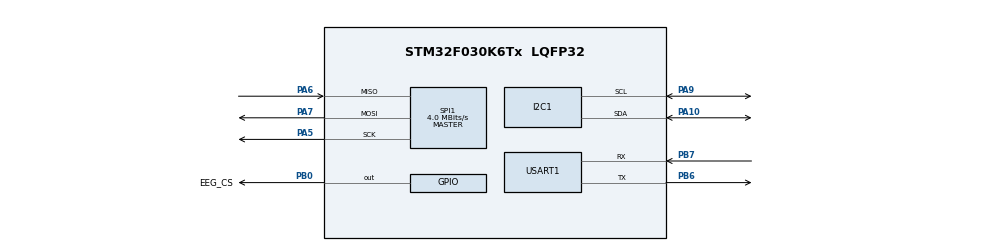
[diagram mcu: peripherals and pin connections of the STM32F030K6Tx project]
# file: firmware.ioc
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Mcu.Family=STM32F0
Mcu.Name=STM32F030K6Tx
Mcu.Package=LQFP32
PA10.Mode=I2C
PA10.Signal=I2C1_SDA
PA5.Mode=Full_Duplex_Master
PA5.Signal=SPI1_SCK
PA6.Mode=Full_Duplex_Master
PA6.Signal=SPI1_MISO
PA7.Mode=Full_Duplex_Master
PA7.Signal=SPI1_MOSI
PA9.Mode=I2C
PA9.Signal=I2C1_SCL
PB0.GPIO_Label=EEG_CS
PB0.Signal=GPIO_Output
PB6.Mode=Asynchronous
PB6.Signal=USART1_TX
PB7.Mode=Asynchronous
PB7.Signal=USART1_RX
ProjectManager.HeapSize=0x200
ProjectManager.StackSize=0x400
ProjectManager.TargetToolchain=Makefile
SPI1.CalculateBaudRate=4.0 MBits/s
SPI1.Direction=SPI_DIRECTION_2LINES
SPI1.Mode=SPI_MODE_MASTER
SPI1.VirtualType=VM_MASTER
USART1.VirtualMode-Asynchronous=VM_ASYNC
board=custom

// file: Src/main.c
/* USER CODE BEGIN Header */
/**
  ******************************************************************************
  * @file           : main.c
  * @brief          : Main program body
  ******************************************************************************
  ** This notice applies to any and all portions of this file
  * that are not between comment pairs USER CODE BEGIN and
  * USER CODE END. Other portions of this file, whether
  * inserted by the user or by software development tools
  * are owned by their respective copyright owners.
  *
  * COPYRIGHT(c) 2019 STMicroelectronics
  *
  * Redistribution and use in source and binary forms, with or without modification,
  * are permitted provided that the following conditions are met:
  *   1. Redistributions of source code must retain the above copyright notice,
  *      this list of conditions and the following disclaimer.
  *   2. Redistributions in binary form must reproduce the above copyright notice,
  *      this list of conditions and the following disclaimer in the documentation
  *      and/or other materials provided with the distribution.
  *   3. Neither the name of STMicroelectronics nor the names of its contributors
  *      may be used to endorse or promote products derived from this software
  *      without specific prior written permission.
  *
  * THIS SOFTWARE IS PROVIDED BY THE COPYRIGHT HOLDERS AND CONTRIBUTORS "AS IS"
  * AND ANY EXPRESS OR IMPLIED WARRANTIES, INCLUDING, BUT NOT LIMITED TO, THE
  * IMPLIED WARRANTIES OF MERCHANTABILITY AND FITNESS FOR A PARTICULAR PURPOSE ARE
  * DISCLAIMED. IN NO EVENT SHALL THE COPYRIGHT HOLDER OR CONTRIBUTORS BE LIABLE
  * FOR ANY DIRECT, INDIRECT, INCIDENTAL, SPECIAL, EXEMPLARY, OR CONSEQUENTIAL
  * DAMAGES (INCLUDING, BUT NOT LIMITED TO, PROCUREMENT OF SUBSTITUTE GOODS OR
  * SERVICES; LOSS OF USE, DATA, OR PROFITS; OR BUSINESS INTERRUPTION) HOWEVER
  * CAUSED AND ON ANY THEORY OF LIABILITY, WHETHER IN CONTRACT, STRICT LIABILITY,
  * OR TORT (INCLUDING NEGLIGENCE OR OTHERWISE) ARISING IN ANY WAY OUT OF THE USE
  * OF THIS SOFTWARE, EVEN IF ADVISED OF THE POSSIBILITY OF SUCH DAMAGE.
  *
  ******************************************************************************
  */
/* USER CODE END Header */

#include "main.h"

I2C_HandleTypeDef hi2c1;

SPI_HandleTypeDef hspi1;

UART_HandleTypeDef huart1;

void SystemClock_Config(void);
static void MX_GPIO_Init(void);
static void MX_I2C1_Init(void);
static void MX_SPI1_Init(void);
static void MX_USART1_UART_Init(void);

int main(void)
{

  /* MCU Configuration--------------------------------------------------------*/

  /* Reset of all peripherals, Initializes the Flash interface and the Systick. */
  HAL_Init();

  /* Configure the system clock */
  SystemClock_Config();

  /* Initialize all configured peripherals */
  MX_GPIO_Init();
  MX_I2C1_Init();
  MX_SPI1_Init();
  MX_USART1_UART_Init();

  /* Infinite loop */
  while (1)
  {

  }
}

void SystemClock_Config(void)
{
  RCC_OscInitTypeDef RCC_OscInitStruct = {0};
  RCC_ClkInitTypeDef RCC_ClkInitStruct = {0};
  RCC_PeriphCLKInitTypeDef PeriphClkInit = {0};

  /**Initializes the CPU, AHB and APB busses clocks
  */
  RCC_OscInitStruct.OscillatorType = RCC_OSCILLATORTYPE_HSI;
  RCC_OscInitStruct.HSIState = RCC_HSI_ON;
  RCC_OscInitStruct.HSICalibrationValue = RCC_HSICALIBRATION_DEFAULT;
  RCC_OscInitStruct.PLL.PLLState = RCC_PLL_NONE;
  if (HAL_RCC_OscConfig(&RCC_OscInitStruct) != HAL_OK)
  {
    Error_Handler();
  }
  /**Initializes the CPU, AHB and APB busses clocks
  */
  RCC_ClkInitStruct.ClockType = RCC_CLOCKTYPE_HCLK|RCC_CLOCKTYPE_SYSCLK
                              |RCC_CLOCKTYPE_PCLK1;
  RCC_ClkInitStruct.SYSCLKSource = RCC_SYSCLKSOURCE_HSI;
  RCC_ClkInitStruct.AHBCLKDivider = RCC_SYSCLK_DIV1;
  RCC_ClkInitStruct.APB1CLKDivider = RCC_HCLK_DIV1;

  if (HAL_RCC_ClockConfig(&RCC_ClkInitStruct, FLASH_LATENCY_0) != HAL_OK)
  {
    Error_Handler();
  }
  PeriphClkInit.PeriphClockSelection = RCC_PERIPHCLK_USART1|RCC_PERIPHCLK_I2C1;
  PeriphClkInit.Usart1ClockSelection = RCC_USART1CLKSOURCE_PCLK1;
  PeriphClkInit.I2c1ClockSelection = RCC_I2C1CLKSOURCE_HSI;
  if (HAL_RCCEx_PeriphCLKConfig(&PeriphClkInit) != HAL_OK)
  {
    Error_Handler();
  }
}

static void MX_I2C1_Init(void)
{

  hi2c1.Instance = I2C1;
  hi2c1.Init.Timing = 0x2000090E;
  hi2c1.Init.OwnAddress1 = 0;
  hi2c1.Init.AddressingMode = I2C_ADDRESSINGMODE_7BIT;
  hi2c1.Init.DualAddressMode = I2C_DUALADDRESS_DISABLE;
  hi2c1.Init.OwnAddress2 = 0;
  hi2c1.Init.OwnAddress2Masks = I2C_OA2_NOMASK;
  hi2c1.Init.GeneralCallMode = I2C_GENERALCALL_DISABLE;
  hi2c1.Init.NoStretchMode = I2C_NOSTRETCH_DISABLE;
  if (HAL_I2C_Init(&hi2c1) != HAL_OK)
  {
    Error_Handler();
  }
  /**Configure Analogue filter
  */
  if (HAL_I2CEx_ConfigAnalogFilter(&hi2c1, I2C_ANALOGFILTER_ENABLE) != HAL_OK)
  {
    Error_Handler();
  }
  /**Configure Digital filter
  */
  if (HAL_I2CEx_ConfigDigitalFilter(&hi2c1, 0) != HAL_OK)
  {
    Error_Handler();
  }

}

static void MX_SPI1_Init(void)
{

  /* SPI1 parameter configuration*/
  hspi1.Instance = SPI1;
  hspi1.Init.Mode = SPI_MODE_MASTER;
  hspi1.Init.Direction = SPI_DIRECTION_2LINES;
  hspi1.Init.DataSize = SPI_DATASIZE_4BIT;
  hspi1.Init.CLKPolarity = SPI_POLARITY_LOW;
  hspi1.Init.CLKPhase = SPI_PHASE_1EDGE;
  hspi1.Init.NSS = SPI_NSS_SOFT;
  hspi1.Init.BaudRatePrescaler = SPI_BAUDRATEPRESCALER_2;
  hspi1.Init.FirstBit = SPI_FIRSTBIT_MSB;
  hspi1.Init.TIMode = SPI_TIMODE_DISABLE;
  hspi1.Init.CRCCalculation = SPI_CRCCALCULATION_DISABLE;
  hspi1.Init.CRCPolynomial = 7;
  hspi1.Init.CRCLength = SPI_CRC_LENGTH_DATASIZE;
  hspi1.Init.NSSPMode = SPI_NSS_PULSE_ENABLE;
  if (HAL_SPI_Init(&hspi1) != HAL_OK)
  {
    Error_Handler();
  }

}

static void MX_USART1_UART_Init(void)
{

  huart1.Instance = USART1;
  huart1.Init.BaudRate = 38400;
  huart1.Init.WordLength = UART_WORDLENGTH_8B;
  huart1.Init.StopBits = UART_STOPBITS_1;
  huart1.Init.Parity = UART_PARITY_NONE;
  huart1.Init.Mode = UART_MODE_TX_RX;
  huart1.Init.HwFlowCtl = UART_HWCONTROL_NONE;
  huart1.Init.OverSampling = UART_OVERSAMPLING_16;
  huart1.Init.OneBitSampling = UART_ONE_BIT_SAMPLE_DISABLE;
  huart1.AdvancedInit.AdvFeatureInit = UART_ADVFEATURE_NO_INIT;
  if (HAL_UART_Init(&huart1) != HAL_OK)
  {
    Error_Handler();
  }

}

static void MX_GPIO_Init(void)
{
  GPIO_InitTypeDef GPIO_InitStruct = {0};

  /* GPIO Ports Clock Enable */
  __HAL_RCC_GPIOA_CLK_ENABLE();
  __HAL_RCC_GPIOB_CLK_ENABLE();

  /*Configure GPIO pin Output Level */
  HAL_GPIO_WritePin(GPIOA, ESP_FLASH_MODE_Pin|ESP_ENABLE_Pin|ESP_TX_Pin|ESP_RX_Pin, GPIO_PIN_RESET);

  /*Configure GPIO pin Output Level */
  HAL_GPIO_WritePin(GPIOB, EEG_CS_Pin|CS_ESP_Pin, GPIO_PIN_RESET);

  /*Configure GPIO pins : ESP_FLASH_MODE_Pin ESP_ENABLE_Pin ESP_TX_Pin ESP_RX_Pin */
  GPIO_InitStruct.Pin = ESP_FLASH_MODE_Pin|ESP_ENABLE_Pin|ESP_TX_Pin|ESP_RX_Pin;
  GPIO_InitStruct.Mode = GPIO_MODE_OUTPUT_PP;
  GPIO_InitStruct.Pull = GPIO_NOPULL;
  GPIO_InitStruct.Speed = GPIO_SPEED_FREQ_LOW;
  HAL_GPIO_Init(GPIOA, &GPIO_InitStruct);

  /*Configure GPIO pins : EEG_CS_Pin CS_ESP_Pin */
  GPIO_InitStruct.Pin = EEG_CS_Pin|CS_ESP_Pin;
  GPIO_InitStruct.Mode = GPIO_MODE_OUTPUT_PP;
  GPIO_InitStruct.Pull = GPIO_NOPULL;
  GPIO_InitStruct.Speed = GPIO_SPEED_FREQ_LOW;
  HAL_GPIO_Init(GPIOB, &GPIO_InitStruct);

}

void Error_Handler(void)
{
}

/************************ (C) COPYRIGHT STMicroelectronics *****END OF FILE****/
